VERSION 5.7 ;
  NOWIREEXTENSIONATPIN ON ;
  DIVIDERCHAR "/" ;
  BUSBITCHARS "[]" ;
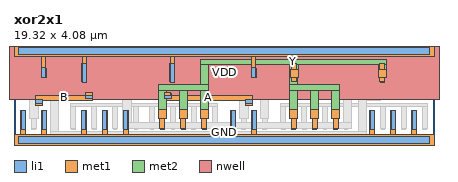
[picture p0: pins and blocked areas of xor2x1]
MACRO xor2x1
  CLASS BLOCK ;
  FOREIGN xor2x1 ;
  ORIGIN 0.000 0.000 ;
  SIZE 19.320 BY 4.080 ;
  PIN B
    ANTENNAGATEAREA 1.323000 ;
    PORT
      LAYER li1 ;
        RECT 3.285 1.930 3.615 2.120 ;
        RECT 0.985 1.660 1.315 1.850 ;
      LAYER met1 ;
        RECT 3.300 2.070 3.600 2.190 ;
        RECT 1.000 1.830 3.600 2.070 ;
        RECT 1.000 1.600 1.300 1.830 ;
    END
  END B
  PIN A
    ANTENNAGATEAREA 1.323000 ;
    PORT
      LAYER li1 ;
        RECT 6.905 1.930 7.235 2.120 ;
        RECT 10.645 1.660 10.975 1.850 ;
      LAYER met1 ;
        RECT 6.920 2.070 7.220 2.190 ;
        RECT 6.920 1.830 10.960 2.070 ;
        RECT 10.660 1.600 10.960 1.830 ;
    END
  END A
  PIN Y
    ANTENNADIFFAREA 2.150400 ;
    PORT
      LAYER li1 ;
        RECT 12.805 2.660 12.975 3.540 ;
        RECT 16.865 2.660 17.035 3.540 ;
        RECT 6.745 0.490 6.915 1.370 ;
        RECT 7.705 0.490 7.875 1.370 ;
        RECT 8.665 0.490 8.835 1.370 ;
        RECT 12.785 0.490 12.955 1.370 ;
        RECT 13.745 0.490 13.915 1.370 ;
        RECT 14.705 0.490 14.875 1.370 ;
      LAYER met1 ;
        RECT 12.775 3.260 13.005 3.520 ;
        RECT 16.835 3.260 17.065 3.520 ;
        RECT 12.710 2.880 13.070 3.260 ;
        RECT 16.770 2.880 17.130 3.260 ;
        RECT 12.775 2.680 13.005 2.880 ;
        RECT 16.835 2.680 17.065 2.880 ;
        RECT 6.640 1.010 7.020 1.390 ;
        RECT 7.600 1.010 7.980 1.390 ;
        RECT 8.560 1.010 8.940 1.390 ;
        RECT 12.680 1.010 13.060 1.390 ;
        RECT 13.640 1.010 14.020 1.390 ;
        RECT 14.600 1.010 14.980 1.390 ;
        RECT 6.715 0.510 6.945 1.010 ;
        RECT 7.675 0.510 7.905 1.010 ;
        RECT 8.635 0.510 8.865 1.010 ;
        RECT 12.755 0.510 12.985 1.010 ;
        RECT 13.715 0.510 13.945 1.010 ;
        RECT 14.675 0.510 14.905 1.010 ;
      LAYER met2 ;
        RECT 8.560 3.460 17.140 3.720 ;
        RECT 8.560 2.560 8.940 3.460 ;
        RECT 6.640 2.300 8.940 2.560 ;
        RECT 6.640 1.010 7.020 2.300 ;
        RECT 7.600 1.010 7.980 2.300 ;
        RECT 8.560 1.010 8.940 2.300 ;
        RECT 12.680 2.880 13.080 3.460 ;
        RECT 16.760 2.880 17.140 3.460 ;
        RECT 12.680 2.560 13.060 2.880 ;
        RECT 12.680 2.300 14.980 2.560 ;
        RECT 12.680 1.010 13.060 2.300 ;
        RECT 13.640 1.010 14.020 2.300 ;
        RECT 14.600 1.010 14.980 2.300 ;
    END
  END Y
  PIN VDD
    ANTENNADIFFAREA 6.229200 ;
    PORT
      LAYER nwell ;
        RECT -0.230 1.870 19.550 4.410 ;
      LAYER li1 ;
        RECT 0.210 3.915 19.110 4.245 ;
        RECT 1.285 2.870 1.455 3.330 ;
        RECT 3.145 2.660 3.315 3.540 ;
        RECT 7.205 2.660 7.375 3.540 ;
        RECT 10.945 2.870 11.115 3.330 ;
      LAYER met1 ;
        RECT 0.000 3.840 19.320 4.320 ;
        RECT 1.285 3.310 1.455 3.840 ;
        RECT 3.145 3.520 3.315 3.840 ;
        RECT 7.205 3.520 7.375 3.840 ;
        RECT 1.255 2.890 1.485 3.310 ;
        RECT 3.115 2.680 3.345 3.520 ;
        RECT 7.175 2.680 7.405 3.520 ;
        RECT 10.945 3.310 11.115 3.840 ;
        RECT 10.915 2.890 11.145 3.310 ;
    END
  END VDD
  PIN GND
    ANTENNADIFFAREA 8.236800 ;
    PORT
      LAYER li1 ;
        RECT 0.345 0.490 0.515 1.370 ;
        RECT 1.305 0.490 1.475 1.370 ;
        RECT 3.125 0.490 3.295 1.370 ;
        RECT 4.085 0.490 4.255 1.370 ;
        RECT 5.045 0.490 5.215 1.370 ;
        RECT 10.005 0.490 10.175 1.370 ;
        RECT 10.965 0.490 11.135 1.370 ;
        RECT 16.405 0.490 16.575 1.370 ;
        RECT 17.365 0.490 17.535 1.370 ;
        RECT 18.325 0.490 18.495 1.370 ;
        RECT 0.210 -0.165 19.110 0.165 ;
      LAYER met1 ;
        RECT 0.315 0.240 0.545 1.350 ;
        RECT 1.275 0.240 1.505 1.350 ;
        RECT 3.095 0.240 3.325 1.350 ;
        RECT 4.055 0.240 4.285 1.350 ;
        RECT 5.015 0.240 5.245 1.350 ;
        RECT 9.975 0.240 10.205 1.350 ;
        RECT 10.935 0.240 11.165 1.350 ;
        RECT 16.375 0.240 16.605 1.350 ;
        RECT 17.335 0.240 17.565 1.350 ;
        RECT 18.295 0.240 18.525 1.350 ;
        RECT 0.000 -0.240 19.320 0.240 ;
    END
  END GND
  OBS
      LAYER li1 ;
        RECT 0.845 2.870 1.015 3.330 ;
        RECT 3.585 2.660 3.755 3.540 ;
        RECT 6.765 2.660 6.935 3.540 ;
        RECT 10.505 2.870 10.675 3.330 ;
        RECT 13.245 2.660 13.415 3.540 ;
        RECT 16.425 2.660 16.595 3.540 ;
        RECT 12.945 1.930 13.275 2.120 ;
        RECT 16.565 1.930 16.895 2.120 ;
        RECT 0.825 0.490 0.995 1.370 ;
        RECT 1.785 0.490 1.955 1.370 ;
        RECT 2.645 0.490 2.815 1.370 ;
        RECT 3.605 0.490 3.775 1.370 ;
        RECT 4.565 0.490 4.735 1.370 ;
        RECT 5.525 0.490 5.695 1.370 ;
        RECT 6.265 0.490 6.435 1.370 ;
        RECT 7.225 0.490 7.395 1.370 ;
        RECT 8.185 0.490 8.355 1.370 ;
        RECT 9.145 0.490 9.315 1.370 ;
        RECT 10.485 0.490 10.655 1.370 ;
        RECT 11.445 0.490 11.615 1.370 ;
        RECT 12.305 0.490 12.475 1.370 ;
        RECT 13.265 0.490 13.435 1.370 ;
        RECT 14.225 0.490 14.395 1.370 ;
        RECT 15.185 0.490 15.355 1.370 ;
        RECT 15.925 0.490 16.095 1.370 ;
        RECT 16.885 0.490 17.055 1.370 ;
        RECT 17.845 0.490 18.015 1.370 ;
        RECT 18.805 0.490 18.975 1.370 ;
      LAYER met1 ;
        RECT 0.815 3.260 1.045 3.310 ;
        RECT 0.740 2.880 1.100 3.260 ;
        RECT 3.555 3.200 3.785 3.520 ;
        RECT 5.010 3.200 5.390 3.290 ;
        RECT 6.735 3.200 6.965 3.520 ;
        RECT 10.475 3.260 10.705 3.310 ;
        RECT 3.555 3.000 6.965 3.200 ;
        RECT 3.555 2.680 3.785 3.000 ;
        RECT 5.010 2.910 5.390 3.000 ;
        RECT 6.735 2.680 6.965 3.000 ;
        RECT 10.400 2.880 10.760 3.260 ;
        RECT 13.215 3.200 13.445 3.520 ;
        RECT 15.140 3.200 15.520 3.290 ;
        RECT 16.395 3.200 16.625 3.520 ;
        RECT 13.215 3.000 16.625 3.200 ;
        RECT 13.215 2.680 13.445 3.000 ;
        RECT 15.140 2.910 15.520 3.000 ;
        RECT 16.395 2.680 16.625 3.000 ;
        RECT 0.720 2.210 2.060 2.590 ;
        RECT 10.380 2.520 11.720 2.590 ;
        RECT 10.380 2.210 13.260 2.520 ;
        RECT 11.720 2.140 13.260 2.210 ;
        RECT 12.960 1.870 13.260 2.140 ;
        RECT 15.825 2.070 16.205 2.210 ;
        RECT 16.580 2.070 16.880 2.190 ;
        RECT 15.825 1.830 16.880 2.070 ;
        RECT 2.615 1.540 9.345 1.690 ;
        RECT 0.720 1.010 1.100 1.390 ;
        RECT 1.680 1.010 2.060 1.390 ;
        RECT 0.795 0.510 1.025 1.010 ;
        RECT 1.755 0.510 1.985 1.010 ;
        RECT 2.615 0.510 2.845 1.540 ;
        RECT 3.575 0.510 3.805 1.540 ;
        RECT 4.535 0.510 4.765 1.540 ;
        RECT 5.495 0.510 5.725 1.540 ;
        RECT 6.235 0.510 6.465 1.540 ;
        RECT 7.195 0.510 7.425 1.540 ;
        RECT 8.155 0.510 8.385 1.540 ;
        RECT 9.115 0.510 9.345 1.540 ;
        RECT 12.275 1.540 19.005 1.690 ;
        RECT 10.380 1.010 10.760 1.390 ;
        RECT 11.340 1.010 11.720 1.390 ;
        RECT 10.455 0.510 10.685 1.010 ;
        RECT 11.415 0.510 11.645 1.010 ;
        RECT 12.275 0.510 12.505 1.540 ;
        RECT 13.235 0.510 13.465 1.540 ;
        RECT 14.195 0.510 14.425 1.540 ;
        RECT 15.155 0.510 15.385 1.540 ;
        RECT 15.895 0.510 16.125 1.540 ;
        RECT 16.855 0.510 17.085 1.540 ;
        RECT 17.815 0.510 18.045 1.540 ;
        RECT 18.775 0.510 19.005 1.540 ;
      LAYER met2 ;
        RECT 0.720 1.010 1.110 3.260 ;
        RECT 1.680 0.400 2.060 2.590 ;
        RECT 5.010 0.800 5.390 3.230 ;
        RECT 10.380 1.010 10.770 3.260 ;
        RECT 11.340 1.010 11.720 2.590 ;
        RECT 15.140 0.800 15.520 3.230 ;
        RECT 5.010 0.540 15.520 0.800 ;
        RECT 15.825 0.400 16.205 2.150 ;
        RECT 1.680 0.140 16.205 0.400 ;
  END
END xor2x1
END LIBRARY

